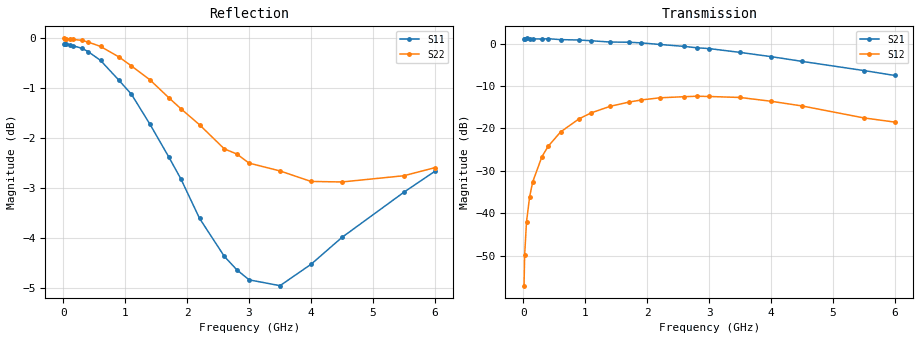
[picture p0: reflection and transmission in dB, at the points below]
! SIEMENS Small Signal Semiconductors
! BFP181
! Si NPN RF Bipolar Junction Transistor in SOT143
! VCE = 1.5 V  IC = 0.3 mA
! Common Emitter S-Parameters:  March  1996
# GHz  S  MA  R  50
!  f  S11  S21  S12  S22
! GHz  MAG  ANG  MAG  ANG  MAG  ANG  MAG  ANG
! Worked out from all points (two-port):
!   36 points, 10 MHz to 6 GHz, reference 50 ohm
!   highest |S21| = 1.23 dB at 50 MHz (marker M1); lowest = -7.5 dB at 6 GHz (marker M2)
!   |S21| within 3 dB of the highest: start of sweep to 3.328 GHz
!   lowest |S11| = -5.0 dB at 3.5 GHz (marker M3), VSWR 3.60, Z = 14.1 + j6.31 ohm
!   |S11| at or under -10 dB: nowhere
!   |S22| runs from -2.9 to 0.0 dB; largest |S21 - S12| = 1.2
!   S11 on the Smith chart (normalised r, x): 10 MHz: open; 900 MHz: 0.33, -2.38; 1.7 GHz: 0.28, -1.01; 2.8 GHz: 0.27, -0.22; 4 GHz: 0.28, +0.33; 6 GHz: 0.31, +0.99
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0.01  0.9871 -0.6  1.124 179.9  0.0014 87.6  0.9997 -0.2
0.02  0.9863 -1.1  1.133 179.7  0.0032 87.8  0.9992 -0.5
0.05  0.9876 -2.3  1.152 177.5  0.0079 92.4  0.9985 -1.3
0.1  0.9843 -5.1  1.125 174.8  0.0155 84.5  0.9984 -2.5
0.15  0.983 -7.4  1.137 172.3  0.0234 83.9  0.9974 -3.7
0.3  0.9771 -15.1  1.131 165.0  0.0466 78.9  0.995 -7.5
0.4  0.9696 -19.9  1.141 158.7  0.0615 75.4  0.9912 -10.0
0.6  0.9502 -29.9  1.114 148.8  0.0908 67.5  0.9813 -15.0
0.9  0.9073 -45.0  1.101 133.6  0.1299 56.6  0.9576 -22.2
1.1  0.8788 -55.2  1.079 124.1  0.153 49.7  0.9381 -26.7
1.4  0.8199 -70.7  1.043 110.3  0.182 39.5  0.9084 -33.4
1.7  0.7611 -87.4  1.037 96.7  0.204 30.3  0.8722 -39.4
1.9  0.7227 -98.9  1.02 87.7  0.2162 24.3  0.8498 -43.2
2.2  0.6601 -116.4  0.977 74.3  0.2295 16.0  0.8191 -48.5
2.6  0.6048 -141.4  0.926 59.0  0.2365 5.7  0.7748 -55.2
2.8  0.5865 -153.6  0.892 50.8  0.2395 0.5  0.7659 -58.5
3  0.5729 -166.2  0.873 43.3  0.2379 -4.7  0.7498 -62.0
3.5  0.5652 164.4  0.787 25.9  0.2316 -15.4  0.7364 -70.3
4  0.5937 141.1  0.702 10.8  0.209 -24.7  0.7188 -80.0
4.5  0.6317 122.4  0.617 -2.1  0.1841 -32.1  0.7179 -90.7
5.5  0.701 97.0  0.481 -21.7  0.133 -34.2  0.7283 -112.9
6  0.7357 88.1  0.421 -29.1  0.1187 -29.8  0.7419 -124.4
